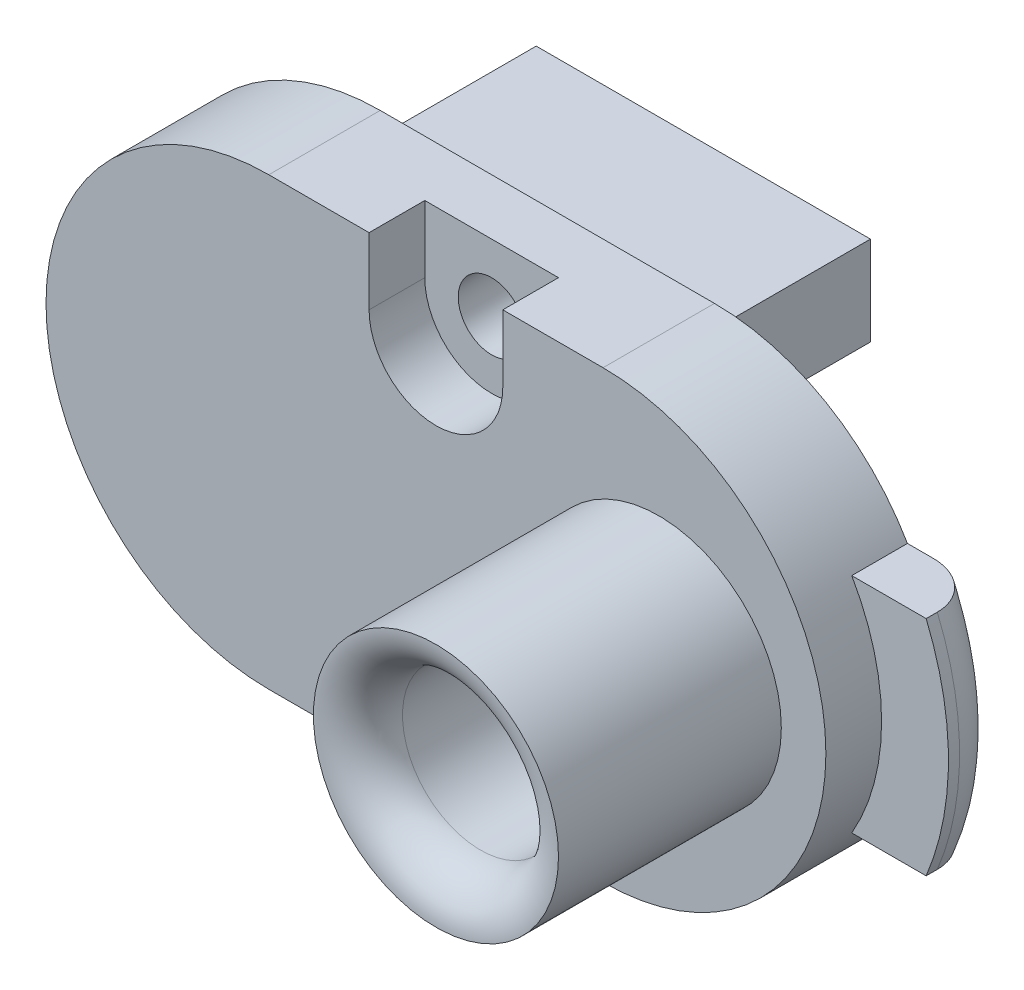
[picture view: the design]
ISO-10303-21;
HEADER;
FILE_DESCRIPTION(('STEP AP214'),'2;1');
FILE_NAME('part.step','',(''),(''),'','','');
FILE_SCHEMA(('AUTOMOTIVE_DESIGN { 1 0 10303 214 1 1 1 1 }'));
ENDSEC;
DATA;
#1=APPLICATION_CONTEXT('core data for automotive mechanical design processes');
#2=APPLICATION_PROTOCOL_DEFINITION('international standard','automotive_design',2000,#1);
#3=PRODUCT_CONTEXT('',#1,'mechanical');
#4=PRODUCT('Part','Part','',(#3));
#5=PRODUCT_RELATED_PRODUCT_CATEGORY('part','',(#4));
#6=PRODUCT_DEFINITION_FORMATION('','',#4);
#7=PRODUCT_DEFINITION_CONTEXT('part definition',#1,'design');
#8=PRODUCT_DEFINITION('design','',#6,#7);
#9=PRODUCT_DEFINITION_SHAPE('','',#8);
#10=(LENGTH_UNIT() NAMED_UNIT(*) SI_UNIT(.MILLI.,.METRE.));
#11=(NAMED_UNIT(*) PLANE_ANGLE_UNIT() SI_UNIT($,.RADIAN.));
#12=(NAMED_UNIT(*) SI_UNIT($,.STERADIAN.) SOLID_ANGLE_UNIT());
#13=UNCERTAINTY_MEASURE_WITH_UNIT(LENGTH_MEASURE(1.E-05),#10,'distance_accuracy_value','');
#14=(GEOMETRIC_REPRESENTATION_CONTEXT(3) GLOBAL_UNCERTAINTY_ASSIGNED_CONTEXT((#13)) GLOBAL_UNIT_ASSIGNED_CONTEXT((#10,
#11,#12)) REPRESENTATION_CONTEXT('',''));
#15=CARTESIAN_POINT('',(0.,0.,0.));
#16=DIRECTION('',(0.,0.,1.));
#17=DIRECTION('',(1.,0.,0.));
#18=AXIS2_PLACEMENT_3D('',#15,#16,#17);
#19=CARTESIAN_POINT('',(7.5,-9.,-9.5));
#20=DIRECTION('',(-1.,0.,0.));
#21=DIRECTION('',(0.,0.,1.));
#22=AXIS2_PLACEMENT_3D('',#19,#20,#21);
#23=PLANE('',#22);
#24=DIRECTION('',(0.,-1.,0.));
#25=VECTOR('',#24,1.);
#26=CARTESIAN_POINT('',(7.5,-5.,-4.5));
#27=LINE('',#26,#25);
#28=CARTESIAN_POINT('',(7.5,-4.89897948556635,-4.5));
#29=VERTEX_POINT('',#28);
#30=CARTESIAN_POINT('',(7.5,-5.,-4.5));
#31=VERTEX_POINT('',#30);
#32=EDGE_CURVE('E346',#29,#31,#27,.T.);
#33=ORIENTED_EDGE('',*,*,#32,.F.);
#34=DIRECTION('',(0.,0.,-1.));
#35=VECTOR('',#34,1.);
#36=CARTESIAN_POINT('',(7.5,-4.89897948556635,13.056349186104));
#37=LINE('',#36,#35);
#38=CARTESIAN_POINT('',(7.5,-4.89897948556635,-2.5));
#39=VERTEX_POINT('',#38);
#40=EDGE_CURVE('E285',#29,#39,#37,.F.);
#41=ORIENTED_EDGE('',*,*,#40,.T.);
#42=DIRECTION('',(0.,-1.,0.));
#43=VECTOR('',#42,1.);
#44=CARTESIAN_POINT('',(7.5,-9.,-2.5));
#45=LINE('',#44,#43);
#46=CARTESIAN_POINT('',(7.5,-9.,-2.5));
#47=VERTEX_POINT('',#46);
#48=EDGE_CURVE('E435',#39,#47,#45,.T.);
#49=ORIENTED_EDGE('',*,*,#48,.T.);
#50=DIRECTION('',(0.,0.,1.));
#51=VECTOR('',#50,1.);
#52=CARTESIAN_POINT('',(7.5,-9.,-9.5));
#53=LINE('',#52,#51);
#54=CARTESIAN_POINT('',(7.5,-9.,-9.5));
#55=VERTEX_POINT('',#54);
#56=EDGE_CURVE('E464',#55,#47,#53,.T.);
#57=ORIENTED_EDGE('',*,*,#56,.F.);
#58=DIRECTION('',(0.,-1.,0.));
#59=VECTOR('',#58,1.);
#60=CARTESIAN_POINT('',(7.5,-9.,-9.5));
#61=LINE('',#60,#59);
#62=CARTESIAN_POINT('',(7.5,-5.,-9.5));
#63=VERTEX_POINT('',#62);
#64=EDGE_CURVE('E448',#63,#55,#61,.T.);
#65=ORIENTED_EDGE('',*,*,#64,.F.);
#66=DIRECTION('',(0.,0.,-1.));
#67=VECTOR('',#66,1.);
#68=CARTESIAN_POINT('',(7.5,-5.,-4.5));
#69=LINE('',#68,#67);
#70=EDGE_CURVE('E358',#31,#63,#69,.T.);
#71=ORIENTED_EDGE('',*,*,#70,.F.);
#72=EDGE_LOOP('',(#33,#41,#49,#57,#65,#71));
#73=FACE_BOUND('',#72,.T.);
#74=ADVANCED_FACE('F36',(#73),#23,.F.);
#75=CARTESIAN_POINT('',(7.5,0.,2.5));
#76=DIRECTION('',(0.,0.,1.));
#77=DIRECTION('',(1.,0.,0.));
#78=AXIS2_PLACEMENT_3D('',#75,#76,#77);
#79=PLANE('',#78);
#80=DIRECTION('',(0.,-1.,0.));
#81=VECTOR('',#80,1.);
#82=CARTESIAN_POINT('',(-3.,7.,2.5));
#83=LINE('',#82,#81);
#84=CARTESIAN_POINT('',(-3.,10.,2.5));
#85=VERTEX_POINT('',#84);
#86=CARTESIAN_POINT('',(-3.,7.,2.5));
#87=VERTEX_POINT('',#86);
#88=EDGE_CURVE('E379',#85,#87,#83,.T.);
#89=ORIENTED_EDGE('',*,*,#88,.F.);
#90=DIRECTION('',(-1.,0.,0.));
#91=VECTOR('',#90,1.);
#92=CARTESIAN_POINT('',(-7.5,10.,2.5));
#93=LINE('',#92,#91);
#94=CARTESIAN_POINT('',(-7.5,10.,2.5));
#95=VERTEX_POINT('',#94);
#96=EDGE_CURVE('E481',#85,#95,#93,.T.);
#97=ORIENTED_EDGE('',*,*,#96,.T.);
#98=CARTESIAN_POINT('',(-7.5,0.,2.5));
#99=DIRECTION('',(0.,0.,1.));
#100=DIRECTION('',(1.,0.,0.));
#101=AXIS2_PLACEMENT_3D('',#98,#99,#100);
#102=CIRCLE('',#101,10.);
#103=CARTESIAN_POINT('',(-7.5,-10.,2.5));
#104=VERTEX_POINT('',#103);
#105=EDGE_CURVE('E485',#95,#104,#102,.T.);
#106=ORIENTED_EDGE('',*,*,#105,.T.);
#107=DIRECTION('',(1.,0.,0.));
#108=VECTOR('',#107,1.);
#109=CARTESIAN_POINT('',(-7.5,-10.,2.5));
#110=LINE('',#109,#108);
#111=CARTESIAN_POINT('',(-3.,-10.,2.5));
#112=VERTEX_POINT('',#111);
#113=EDGE_CURVE('E488',#104,#112,#110,.T.);
#114=ORIENTED_EDGE('',*,*,#113,.T.);
#115=DIRECTION('',(0.,-1.,0.));
#116=VECTOR('',#115,1.);
#117=CARTESIAN_POINT('',(-3.,-7.,2.5));
#118=LINE('',#117,#116);
#119=CARTESIAN_POINT('',(-3.,-7.,2.5));
#120=VERTEX_POINT('',#119);
#121=EDGE_CURVE('E409',#120,#112,#118,.T.);
#122=ORIENTED_EDGE('',*,*,#121,.F.);
#123=CARTESIAN_POINT('',(0.,-7.,2.5));
#124=DIRECTION('',(0.,0.,1.));
#125=DIRECTION('',(1.,0.,0.));
#126=AXIS2_PLACEMENT_3D('',#123,#124,#125);
#127=CIRCLE('',#126,3.);
#128=CARTESIAN_POINT('',(3.,-7.,2.5));
#129=VERTEX_POINT('',#128);
#130=EDGE_CURVE('E406',#129,#120,#127,.T.);
#131=ORIENTED_EDGE('',*,*,#130,.F.);
#132=DIRECTION('',(0.,1.,0.));
#133=VECTOR('',#132,1.);
#134=CARTESIAN_POINT('',(3.,-7.,2.5));
#135=LINE('',#134,#133);
#136=CARTESIAN_POINT('',(3.,-10.,2.5));
#137=VERTEX_POINT('',#136);
#138=EDGE_CURVE('E396',#137,#129,#135,.T.);
#139=ORIENTED_EDGE('',*,*,#138,.F.);
#140=CARTESIAN_POINT('',(7.5,-10.,2.5));
#141=VERTEX_POINT('',#140);
#142=EDGE_CURVE('E487',#137,#141,#110,.T.);
#143=ORIENTED_EDGE('',*,*,#142,.T.);
#144=CARTESIAN_POINT('',(7.5,0.,2.5));
#145=DIRECTION('',(0.,0.,1.));
#146=DIRECTION('',(1.,0.,0.));
#147=AXIS2_PLACEMENT_3D('',#144,#145,#146);
#148=CIRCLE('',#147,10.);
#149=CARTESIAN_POINT('',(7.5,10.,2.5));
#150=VERTEX_POINT('',#149);
#151=EDGE_CURVE('E478',#141,#150,#148,.T.);
#152=ORIENTED_EDGE('',*,*,#151,.T.);
#153=CARTESIAN_POINT('',(3.,10.,2.5));
#154=VERTEX_POINT('',#153);
#155=EDGE_CURVE('E482',#150,#154,#93,.T.);
#156=ORIENTED_EDGE('',*,*,#155,.T.);
#157=DIRECTION('',(0.,1.,0.));
#158=VECTOR('',#157,1.);
#159=CARTESIAN_POINT('',(3.,7.,2.5));
#160=LINE('',#159,#158);
#161=CARTESIAN_POINT('',(3.,7.,2.5));
#162=VERTEX_POINT('',#161);
#163=EDGE_CURVE('E377',#162,#154,#160,.T.);
#164=ORIENTED_EDGE('',*,*,#163,.F.);
#165=CARTESIAN_POINT('',(0.,7.,2.5));
#166=DIRECTION('',(0.,0.,1.));
#167=DIRECTION('',(-1.,0.,0.));
#168=AXIS2_PLACEMENT_3D('',#165,#166,#167);
#169=CIRCLE('',#168,3.);
#170=EDGE_CURVE('E375',#87,#162,#169,.T.);
#171=ORIENTED_EDGE('',*,*,#170,.F.);
#172=EDGE_LOOP('',(#89,#97,#106,#114,#122,#131,#139,#143,#152,#156,#164,#171));
#173=FACE_BOUND('',#172,.T.);
#174=CARTESIAN_POINT('',(10.,0.,2.5));
#175=DIRECTION('',(0.,0.,1.));
#176=DIRECTION('',(1.,0.,0.));
#177=AXIS2_PLACEMENT_3D('',#174,#175,#176);
#178=CIRCLE('',#177,5.5);
#179=CARTESIAN_POINT('',(15.5,0.,2.5));
#180=VERTEX_POINT('',#179);
#181=EDGE_CURVE('E288',#180,#180,#178,.T.);
#182=ORIENTED_EDGE('',*,*,#181,.F.);
#183=EDGE_LOOP('',(#182));
#184=FACE_BOUND('',#183,.T.);
#185=ADVANCED_FACE('F653',(#173,#184),#79,.T.);
#186=CARTESIAN_POINT('',(7.5,9.,-9.5));
#187=DIRECTION('',(0.,0.,1.));
#188=DIRECTION('',(1.,0.,0.));
#189=AXIS2_PLACEMENT_3D('',#186,#187,#188);
#190=PLANE('',#189);
#191=CARTESIAN_POINT('',(0.,-7.,-9.5));
#192=DIRECTION('',(0.,0.,1.));
#193=DIRECTION('',(1.,0.,0.));
#194=AXIS2_PLACEMENT_3D('',#191,#192,#193);
#195=CIRCLE('',#194,1.5);
#196=CARTESIAN_POINT('',(1.5,-7.,-9.5));
#197=VERTEX_POINT('',#196);
#198=EDGE_CURVE('E366',#197,#197,#195,.T.);
#199=ORIENTED_EDGE('',*,*,#198,.T.);
#200=EDGE_LOOP('',(#199));
#201=FACE_BOUND('',#200,.T.);
#202=DIRECTION('',(0.,1.,0.));
#203=VECTOR('',#202,1.);
#204=CARTESIAN_POINT('',(-7.5,9.,-9.5));
#205=LINE('',#204,#203);
#206=CARTESIAN_POINT('',(-7.5,-9.,-9.5));
#207=VERTEX_POINT('',#206);
#208=CARTESIAN_POINT('',(-7.5,-5.,-9.5));
#209=VERTEX_POINT('',#208);
#210=EDGE_CURVE('E455',#207,#209,#205,.T.);
#211=ORIENTED_EDGE('',*,*,#210,.T.);
#212=DIRECTION('',(-1.,0.,0.));
#213=VECTOR('',#212,1.);
#214=CARTESIAN_POINT('',(-7.5,-5.,-9.5));
#215=LINE('',#214,#213);
#216=EDGE_CURVE('E338',#63,#209,#215,.T.);
#217=ORIENTED_EDGE('',*,*,#216,.F.);
#218=ORIENTED_EDGE('',*,*,#64,.T.);
#219=DIRECTION('',(-1.,0.,0.));
#220=VECTOR('',#219,1.);
#221=CARTESIAN_POINT('',(7.5,-9.,-9.5));
#222=LINE('',#221,#220);
#223=EDGE_CURVE('E452',#55,#207,#222,.T.);
#224=ORIENTED_EDGE('',*,*,#223,.T.);
#225=EDGE_LOOP('',(#211,#217,#218,#224));
#226=FACE_BOUND('',#225,.T.);
#227=ADVANCED_FACE('F632',(#201,#226),#190,.F.);
#228=CARTESIAN_POINT('',(7.5,0.,-2.5));
#229=DIRECTION('',(0.,0.,1.));
#230=DIRECTION('',(1.,0.,0.));
#231=AXIS2_PLACEMENT_3D('',#228,#229,#230);
#232=PLANE('',#231);
#233=ORIENTED_EDGE('',*,*,#48,.F.);
#234=CARTESIAN_POINT('',(10.,0.,-2.5));
#235=DIRECTION('',(0.,0.,1.));
#236=DIRECTION('',(1.,0.,0.));
#237=AXIS2_PLACEMENT_3D('',#234,#235,#236);
#238=CIRCLE('',#237,5.5);
#239=CARTESIAN_POINT('',(7.5,4.89897948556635,-2.5));
#240=VERTEX_POINT('',#239);
#241=EDGE_CURVE('E514',#39,#240,#238,.T.);
#242=ORIENTED_EDGE('',*,*,#241,.T.);
#243=CARTESIAN_POINT('',(7.5,9.,-2.5));
#244=VERTEX_POINT('',#243);
#245=EDGE_CURVE('E436',#244,#240,#45,.T.);
#246=ORIENTED_EDGE('',*,*,#245,.F.);
#247=DIRECTION('',(1.,0.,0.));
#248=VECTOR('',#247,1.);
#249=CARTESIAN_POINT('',(-7.5,9.,-2.5));
#250=LINE('',#249,#248);
#251=CARTESIAN_POINT('',(-7.5,9.,-2.5));
#252=VERTEX_POINT('',#251);
#253=EDGE_CURVE('E427',#252,#244,#250,.T.);
#254=ORIENTED_EDGE('',*,*,#253,.F.);
#255=CARTESIAN_POINT('',(-7.5,0.,-2.5));
#256=DIRECTION('',(0.,0.,-1.));
#257=DIRECTION('',(1.,0.,0.));
#258=AXIS2_PLACEMENT_3D('',#255,#256,#257);
#259=CIRCLE('',#258,9.);
#260=CARTESIAN_POINT('',(-16.4861003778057,0.5,-2.5));
#261=VERTEX_POINT('',#260);
#262=EDGE_CURVE('E297',#261,#252,#259,.T.);
#263=ORIENTED_EDGE('',*,*,#262,.F.);
#264=DIRECTION('',(-1.,0.,0.));
#265=VECTOR('',#264,1.);
#266=CARTESIAN_POINT('',(-7.5,0.5,-2.5));
#267=LINE('',#266,#265);
#268=CARTESIAN_POINT('',(-7.5,0.5,-2.5));
#269=VERTEX_POINT('',#268);
#270=EDGE_CURVE('E294',#269,#261,#267,.T.);
#271=ORIENTED_EDGE('',*,*,#270,.F.);
#272=DIRECTION('',(0.,1.,0.));
#273=VECTOR('',#272,1.);
#274=CARTESIAN_POINT('',(-7.5,9.,-2.5));
#275=LINE('',#274,#273);
#276=CARTESIAN_POINT('',(-7.5,-0.499999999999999,-2.5));
#277=VERTEX_POINT('',#276);
#278=EDGE_CURVE('E442',#277,#269,#275,.T.);
#279=ORIENTED_EDGE('',*,*,#278,.F.);
#280=DIRECTION('',(1.,0.,0.));
#281=VECTOR('',#280,1.);
#282=CARTESIAN_POINT('',(-7.5,-0.5,-2.5));
#283=LINE('',#282,#281);
#284=CARTESIAN_POINT('',(-16.4861003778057,-0.5,-2.5));
#285=VERTEX_POINT('',#284);
#286=EDGE_CURVE('E318',#285,#277,#283,.T.);
#287=ORIENTED_EDGE('',*,*,#286,.F.);
#288=CARTESIAN_POINT('',(-7.5,0.,-2.5));
#289=DIRECTION('',(0.,0.,-1.));
#290=DIRECTION('',(1.,0.,0.));
#291=AXIS2_PLACEMENT_3D('',#288,#289,#290);
#292=CIRCLE('',#291,9.);
#293=CARTESIAN_POINT('',(-7.5,-9.,-2.5));
#294=VERTEX_POINT('',#293);
#295=EDGE_CURVE('E312',#294,#285,#292,.T.);
#296=ORIENTED_EDGE('',*,*,#295,.F.);
#297=DIRECTION('',(-1.,0.,0.));
#298=VECTOR('',#297,1.);
#299=CARTESIAN_POINT('',(7.5,-9.,-2.5));
#300=LINE('',#299,#298);
#301=EDGE_CURVE('E439',#47,#294,#300,.T.);
#302=ORIENTED_EDGE('',*,*,#301,.F.);
#303=EDGE_LOOP('',(#233,#242,#246,#254,#263,#271,#279,#287,#296,#302));
#304=FACE_BOUND('',#303,.T.);
#305=DIRECTION('',(-1.,0.,0.));
#306=VECTOR('',#305,1.);
#307=CARTESIAN_POINT('',(16.1602540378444,5.,-2.5));
#308=LINE('',#307,#306);
#309=CARTESIAN_POINT('',(17.2979589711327,5.,-2.5));
#310=VERTEX_POINT('',#309);
#311=CARTESIAN_POINT('',(16.1602540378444,5.,-2.5));
#312=VERTEX_POINT('',#311);
#313=EDGE_CURVE('E270',#310,#312,#308,.T.);
#314=ORIENTED_EDGE('',*,*,#313,.F.);
#315=CARTESIAN_POINT('',(7.5,0.,-2.5));
#316=DIRECTION('',(0.,0.,1.));
#317=DIRECTION('',(1.,0.,0.));
#318=AXIS2_PLACEMENT_3D('',#315,#316,#317);
#319=CIRCLE('',#318,11.);
#320=CARTESIAN_POINT('',(17.2979589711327,-5.,-2.5));
#321=VERTEX_POINT('',#320);
#322=EDGE_CURVE('E51',#310,#321,#319,.F.);
#323=ORIENTED_EDGE('',*,*,#322,.T.);
#324=DIRECTION('',(1.,0.,0.));
#325=VECTOR('',#324,1.);
#326=CARTESIAN_POINT('',(16.1602540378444,-5.,-2.5));
#327=LINE('',#326,#325);
#328=CARTESIAN_POINT('',(16.1602540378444,-5.,-2.5));
#329=VERTEX_POINT('',#328);
#330=EDGE_CURVE('E274',#329,#321,#327,.T.);
#331=ORIENTED_EDGE('',*,*,#330,.F.);
#332=CARTESIAN_POINT('',(7.5,0.,-2.5));
#333=DIRECTION('',(0.,0.,1.));
#334=DIRECTION('',(1.,0.,0.));
#335=AXIS2_PLACEMENT_3D('',#332,#333,#334);
#336=CIRCLE('',#335,10.);
#337=CARTESIAN_POINT('',(7.5,-10.,-2.5));
#338=VERTEX_POINT('',#337);
#339=EDGE_CURVE('E269',#338,#329,#336,.T.);
#340=ORIENTED_EDGE('',*,*,#339,.F.);
#341=DIRECTION('',(1.,0.,0.));
#342=VECTOR('',#341,1.);
#343=CARTESIAN_POINT('',(-7.5,-10.,-2.5));
#344=LINE('',#343,#342);
#345=CARTESIAN_POINT('',(-7.5,-10.,-2.5));
#346=VERTEX_POINT('',#345);
#347=EDGE_CURVE('E476',#346,#338,#344,.T.);
#348=ORIENTED_EDGE('',*,*,#347,.F.);
#349=CARTESIAN_POINT('',(-7.5,0.,-2.5));
#350=DIRECTION('',(0.,0.,1.));
#351=DIRECTION('',(1.,0.,0.));
#352=AXIS2_PLACEMENT_3D('',#349,#350,#351);
#353=CIRCLE('',#352,10.);
#354=CARTESIAN_POINT('',(-7.5,10.,-2.5));
#355=VERTEX_POINT('',#354);
#356=EDGE_CURVE('E474',#355,#346,#353,.T.);
#357=ORIENTED_EDGE('',*,*,#356,.F.);
#358=DIRECTION('',(-1.,0.,0.));
#359=VECTOR('',#358,1.);
#360=CARTESIAN_POINT('',(-7.5,10.,-2.5));
#361=LINE('',#360,#359);
#362=CARTESIAN_POINT('',(7.5,10.,-2.5));
#363=VERTEX_POINT('',#362);
#364=EDGE_CURVE('E472',#363,#355,#361,.T.);
#365=ORIENTED_EDGE('',*,*,#364,.F.);
#366=EDGE_CURVE('E470',#312,#363,#336,.T.);
#367=ORIENTED_EDGE('',*,*,#366,.F.);
#368=EDGE_LOOP('',(#314,#323,#331,#340,#348,#357,#365,#367));
#369=FACE_BOUND('',#368,.T.);
#370=ADVANCED_FACE('F649',(#304,#369),#232,.F.);
#371=CARTESIAN_POINT('',(7.5,0.,2.5));
#372=DIRECTION('',(0.,0.,-1.));
#373=DIRECTION('',(-1.,0.,0.));
#374=AXIS2_PLACEMENT_3D('',#371,#372,#373);
#375=CYLINDRICAL_SURFACE('',#374,10.);
#376=CARTESIAN_POINT('',(7.5,0.,0.));
#377=DIRECTION('',(0.,0.,-1.));
#378=DIRECTION('',(1.,0.,0.));
#379=AXIS2_PLACEMENT_3D('',#376,#377,#378);
#380=CIRCLE('',#379,10.);
#381=CARTESIAN_POINT('',(16.1602540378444,5.,0.));
#382=VERTEX_POINT('',#381);
#383=CARTESIAN_POINT('',(16.1602540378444,-5.,0.));
#384=VERTEX_POINT('',#383);
#385=EDGE_CURVE('E256',#382,#384,#380,.T.);
#386=ORIENTED_EDGE('',*,*,#385,.F.);
#387=DIRECTION('',(0.,0.,1.));
#388=VECTOR('',#387,1.);
#389=CARTESIAN_POINT('',(16.1602540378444,5.,-2.5));
#390=LINE('',#389,#388);
#391=EDGE_CURVE('E282',#312,#382,#390,.T.);
#392=ORIENTED_EDGE('',*,*,#391,.F.);
#393=ORIENTED_EDGE('',*,*,#366,.T.);
#394=DIRECTION('',(0.,0.,-1.));
#395=VECTOR('',#394,1.);
#396=CARTESIAN_POINT('',(7.5,10.,2.5));
#397=LINE('',#396,#395);
#398=EDGE_CURVE('E499',#150,#363,#397,.T.);
#399=ORIENTED_EDGE('',*,*,#398,.F.);
#400=ORIENTED_EDGE('',*,*,#151,.F.);
#401=DIRECTION('',(0.,0.,-1.));
#402=VECTOR('',#401,1.);
#403=CARTESIAN_POINT('',(7.5,-10.,2.5));
#404=LINE('',#403,#402);
#405=EDGE_CURVE('E491',#141,#338,#404,.T.);
#406=ORIENTED_EDGE('',*,*,#405,.T.);
#407=ORIENTED_EDGE('',*,*,#339,.T.);
#408=DIRECTION('',(0.,0.,1.));
#409=VECTOR('',#408,1.);
#410=CARTESIAN_POINT('',(16.1602540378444,-5.,-2.5));
#411=LINE('',#410,#409);
#412=EDGE_CURVE('E249',#329,#384,#411,.T.);
#413=ORIENTED_EDGE('',*,*,#412,.T.);
#414=EDGE_LOOP('',(#386,#392,#393,#399,#400,#406,#407,#413));
#415=FACE_BOUND('',#414,.T.);
#416=ADVANCED_FACE('F38',(#415),#375,.T.);
#417=CARTESIAN_POINT('',(-7.5,10.,2.5));
#418=DIRECTION('',(0.,-1.,0.));
#419=DIRECTION('',(0.,0.,-1.));
#420=AXIS2_PLACEMENT_3D('',#417,#418,#419);
#421=PLANE('',#420);
#422=ORIENTED_EDGE('',*,*,#96,.F.);
#423=DIRECTION('',(0.,0.,1.));
#424=VECTOR('',#423,1.);
#425=CARTESIAN_POINT('',(-3.,10.,0.));
#426=LINE('',#425,#424);
#427=CARTESIAN_POINT('',(-3.,10.,0.));
#428=VERTEX_POINT('',#427);
#429=EDGE_CURVE('E397',#428,#85,#426,.T.);
#430=ORIENTED_EDGE('',*,*,#429,.F.);
#431=DIRECTION('',(-1.,0.,0.));
#432=VECTOR('',#431,1.);
#433=CARTESIAN_POINT('',(-3.,10.,0.));
#434=LINE('',#433,#432);
#435=CARTESIAN_POINT('',(3.,10.,0.));
#436=VERTEX_POINT('',#435);
#437=EDGE_CURVE('E388',#436,#428,#434,.T.);
#438=ORIENTED_EDGE('',*,*,#437,.F.);
#439=DIRECTION('',(0.,0.,1.));
#440=VECTOR('',#439,1.);
#441=CARTESIAN_POINT('',(3.,10.,0.));
#442=LINE('',#441,#440);
#443=EDGE_CURVE('E399',#436,#154,#442,.T.);
#444=ORIENTED_EDGE('',*,*,#443,.T.);
#445=ORIENTED_EDGE('',*,*,#155,.F.);
#446=ORIENTED_EDGE('',*,*,#398,.T.);
#447=ORIENTED_EDGE('',*,*,#364,.T.);
#448=DIRECTION('',(0.,0.,-1.));
#449=VECTOR('',#448,1.);
#450=CARTESIAN_POINT('',(-7.5,10.,2.5));
#451=LINE('',#450,#449);
#452=EDGE_CURVE('E496',#95,#355,#451,.T.);
#453=ORIENTED_EDGE('',*,*,#452,.F.);
#454=EDGE_LOOP('',(#422,#430,#438,#444,#445,#446,#447,#453));
#455=FACE_BOUND('',#454,.T.);
#456=ADVANCED_FACE('F662',(#455),#421,.F.);
#457=CARTESIAN_POINT('',(-7.5,0.,2.5));
#458=DIRECTION('',(0.,0.,-1.));
#459=DIRECTION('',(-1.,0.,0.));
#460=AXIS2_PLACEMENT_3D('',#457,#458,#459);
#461=CYLINDRICAL_SURFACE('',#460,10.);
#462=ORIENTED_EDGE('',*,*,#356,.T.);
#463=DIRECTION('',(0.,0.,-1.));
#464=VECTOR('',#463,1.);
#465=CARTESIAN_POINT('',(-7.5,-10.,2.5));
#466=LINE('',#465,#464);
#467=EDGE_CURVE('E493',#104,#346,#466,.T.);
#468=ORIENTED_EDGE('',*,*,#467,.F.);
#469=ORIENTED_EDGE('',*,*,#105,.F.);
#470=ORIENTED_EDGE('',*,*,#452,.T.);
#471=EDGE_LOOP('',(#462,#468,#469,#470));
#472=FACE_BOUND('',#471,.T.);
#473=ADVANCED_FACE('F659',(#472),#461,.T.);
#474=CARTESIAN_POINT('',(-7.5,-10.,2.5));
#475=DIRECTION('',(0.,1.,0.));
#476=DIRECTION('',(0.,0.,1.));
#477=AXIS2_PLACEMENT_3D('',#474,#475,#476);
#478=PLANE('',#477);
#479=DIRECTION('',(1.,0.,0.));
#480=VECTOR('',#479,1.);
#481=CARTESIAN_POINT('',(-3.,-10.,0.));
#482=LINE('',#481,#480);
#483=CARTESIAN_POINT('',(-3.,-10.,0.));
#484=VERTEX_POINT('',#483);
#485=CARTESIAN_POINT('',(3.,-10.,0.));
#486=VERTEX_POINT('',#485);
#487=EDGE_CURVE('E411',#484,#486,#482,.T.);
#488=ORIENTED_EDGE('',*,*,#487,.F.);
#489=DIRECTION('',(0.,0.,1.));
#490=VECTOR('',#489,1.);
#491=CARTESIAN_POINT('',(-3.,-10.,0.));
#492=LINE('',#491,#490);
#493=EDGE_CURVE('E424',#484,#112,#492,.T.);
#494=ORIENTED_EDGE('',*,*,#493,.T.);
#495=ORIENTED_EDGE('',*,*,#113,.F.);
#496=ORIENTED_EDGE('',*,*,#467,.T.);
#497=ORIENTED_EDGE('',*,*,#347,.T.);
#498=ORIENTED_EDGE('',*,*,#405,.F.);
#499=ORIENTED_EDGE('',*,*,#142,.F.);
#500=DIRECTION('',(0.,0.,1.));
#501=VECTOR('',#500,1.);
#502=CARTESIAN_POINT('',(3.,-10.,0.));
#503=LINE('',#502,#501);
#504=EDGE_CURVE('E423',#486,#137,#503,.T.);
#505=ORIENTED_EDGE('',*,*,#504,.F.);
#506=EDGE_LOOP('',(#488,#494,#495,#496,#497,#498,#499,#505));
#507=FACE_BOUND('',#506,.T.);
#508=ADVANCED_FACE('F647',(#507),#478,.F.);
#509=CARTESIAN_POINT('',(-7.5,9.,-9.5));
#510=DIRECTION('',(0.,-1.,0.));
#511=DIRECTION('',(0.,0.,-1.));
#512=AXIS2_PLACEMENT_3D('',#509,#510,#511);
#513=PLANE('',#512);
#514=ORIENTED_EDGE('',*,*,#253,.T.);
#515=DIRECTION('',(0.,0.,1.));
#516=VECTOR('',#515,1.);
#517=CARTESIAN_POINT('',(7.5,9.,-9.5));
#518=LINE('',#517,#516);
#519=CARTESIAN_POINT('',(7.5,9.,-9.5));
#520=VERTEX_POINT('',#519);
#521=EDGE_CURVE('E467',#520,#244,#518,.T.);
#522=ORIENTED_EDGE('',*,*,#521,.F.);
#523=DIRECTION('',(1.,0.,0.));
#524=VECTOR('',#523,1.);
#525=CARTESIAN_POINT('',(-7.5,9.,-9.5));
#526=LINE('',#525,#524);
#527=CARTESIAN_POINT('',(-7.5,9.,-9.5));
#528=VERTEX_POINT('',#527);
#529=EDGE_CURVE('E445',#528,#520,#526,.T.);
#530=ORIENTED_EDGE('',*,*,#529,.F.);
#531=DIRECTION('',(0.,0.,1.));
#532=VECTOR('',#531,1.);
#533=CARTESIAN_POINT('',(-7.5,9.,-9.5));
#534=LINE('',#533,#532);
#535=EDGE_CURVE('E458',#528,#252,#534,.T.);
#536=ORIENTED_EDGE('',*,*,#535,.T.);
#537=EDGE_LOOP('',(#514,#522,#530,#536));
#538=FACE_BOUND('',#537,.T.);
#539=ADVANCED_FACE('F643',(#538),#513,.F.);
#540=ORIENTED_EDGE('',*,*,#245,.T.);
#541=DIRECTION('',(0.,0.,-1.));
#542=VECTOR('',#541,1.);
#543=CARTESIAN_POINT('',(7.5,4.89897948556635,13.056349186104));
#544=LINE('',#543,#542);
#545=CARTESIAN_POINT('',(7.5,4.89897948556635,-4.5));
#546=VERTEX_POINT('',#545);
#547=EDGE_CURVE('E281',#240,#546,#544,.T.);
#548=ORIENTED_EDGE('',*,*,#547,.T.);
#549=CARTESIAN_POINT('',(7.5,5.,-4.5));
#550=VERTEX_POINT('',#549);
#551=EDGE_CURVE('E347',#550,#546,#27,.T.);
#552=ORIENTED_EDGE('',*,*,#551,.F.);
#553=DIRECTION('',(0.,0.,-1.));
#554=VECTOR('',#553,1.);
#555=CARTESIAN_POINT('',(7.5,5.,-4.5));
#556=LINE('',#555,#554);
#557=CARTESIAN_POINT('',(7.5,5.,-9.5));
#558=VERTEX_POINT('',#557);
#559=EDGE_CURVE('E360',#550,#558,#556,.T.);
#560=ORIENTED_EDGE('',*,*,#559,.T.);
#561=EDGE_CURVE('E449',#520,#558,#61,.T.);
#562=ORIENTED_EDGE('',*,*,#561,.F.);
#563=ORIENTED_EDGE('',*,*,#521,.T.);
#564=EDGE_LOOP('',(#540,#548,#552,#560,#562,#563));
#565=FACE_BOUND('',#564,.T.);
#566=ADVANCED_FACE('F639',(#565),#23,.F.);
#567=CARTESIAN_POINT('',(7.5,-9.,-9.5));
#568=DIRECTION('',(0.,1.,0.));
#569=DIRECTION('',(0.,0.,1.));
#570=AXIS2_PLACEMENT_3D('',#567,#568,#569);
#571=PLANE('',#570);
#572=ORIENTED_EDGE('',*,*,#301,.T.);
#573=DIRECTION('',(0.,0.,1.));
#574=VECTOR('',#573,1.);
#575=CARTESIAN_POINT('',(-7.5,-9.,-9.5));
#576=LINE('',#575,#574);
#577=EDGE_CURVE('E461',#207,#294,#576,.T.);
#578=ORIENTED_EDGE('',*,*,#577,.F.);
#579=ORIENTED_EDGE('',*,*,#223,.F.);
#580=ORIENTED_EDGE('',*,*,#56,.T.);
#581=EDGE_LOOP('',(#572,#578,#579,#580));
#582=FACE_BOUND('',#581,.T.);
#583=ADVANCED_FACE('F635',(#582),#571,.F.);
#584=CARTESIAN_POINT('',(-7.5,9.,-9.5));
#585=DIRECTION('',(1.,0.,0.));
#586=DIRECTION('',(0.,1.,0.));
#587=AXIS2_PLACEMENT_3D('',#584,#585,#586);
#588=PLANE('',#587);
#589=DIRECTION('',(0.,1.,0.));
#590=VECTOR('',#589,1.);
#591=CARTESIAN_POINT('',(-7.5,-5.,-4.5));
#592=LINE('',#591,#590);
#593=CARTESIAN_POINT('',(-7.5,-5.,-4.5));
#594=VERTEX_POINT('',#593);
#595=CARTESIAN_POINT('',(-7.5,5.,-4.5));
#596=VERTEX_POINT('',#595);
#597=EDGE_CURVE('E340',#594,#596,#592,.T.);
#598=ORIENTED_EDGE('',*,*,#597,.F.);
#599=DIRECTION('',(0.,0.,-1.));
#600=VECTOR('',#599,1.);
#601=CARTESIAN_POINT('',(-7.5,-5.,-4.5));
#602=LINE('',#601,#600);
#603=EDGE_CURVE('E354',#594,#209,#602,.T.);
#604=ORIENTED_EDGE('',*,*,#603,.T.);
#605=ORIENTED_EDGE('',*,*,#210,.F.);
#606=ORIENTED_EDGE('',*,*,#577,.T.);
#607=DIRECTION('',(0.,0.,-1.));
#608=VECTOR('',#607,1.);
#609=CARTESIAN_POINT('',(-7.5,-9.,-0.5));
#610=LINE('',#609,#608);
#611=CARTESIAN_POINT('',(-7.5,-9.,-0.5));
#612=VERTEX_POINT('',#611);
#613=EDGE_CURVE('E330',#612,#294,#610,.T.);
#614=ORIENTED_EDGE('',*,*,#613,.F.);
#615=DIRECTION('',(0.,-1.,0.));
#616=VECTOR('',#615,1.);
#617=CARTESIAN_POINT('',(-7.5,-9.,-0.5));
#618=LINE('',#617,#616);
#619=CARTESIAN_POINT('',(-7.5,-0.5,-0.5));
#620=VERTEX_POINT('',#619);
#621=EDGE_CURVE('E326',#620,#612,#618,.T.);
#622=ORIENTED_EDGE('',*,*,#621,.F.);
#623=DIRECTION('',(0.,0.,-1.));
#624=VECTOR('',#623,1.);
#625=CARTESIAN_POINT('',(-7.5,-0.5,-0.5));
#626=LINE('',#625,#624);
#627=EDGE_CURVE('E333',#620,#277,#626,.T.);
#628=ORIENTED_EDGE('',*,*,#627,.T.);
#629=ORIENTED_EDGE('',*,*,#278,.T.);
#630=DIRECTION('',(0.,0.,-1.));
#631=VECTOR('',#630,1.);
#632=CARTESIAN_POINT('',(-7.5,0.5,-0.5));
#633=LINE('',#632,#631);
#634=CARTESIAN_POINT('',(-7.5,0.5,-0.5));
#635=VERTEX_POINT('',#634);
#636=EDGE_CURVE('E308',#635,#269,#633,.T.);
#637=ORIENTED_EDGE('',*,*,#636,.F.);
#638=DIRECTION('',(0.,-1.,0.));
#639=VECTOR('',#638,1.);
#640=CARTESIAN_POINT('',(-7.5,0.5,-0.5));
#641=LINE('',#640,#639);
#642=CARTESIAN_POINT('',(-7.5,9.,-0.5));
#643=VERTEX_POINT('',#642);
#644=EDGE_CURVE('E299',#643,#635,#641,.T.);
#645=ORIENTED_EDGE('',*,*,#644,.F.);
#646=DIRECTION('',(0.,0.,-1.));
#647=VECTOR('',#646,1.);
#648=CARTESIAN_POINT('',(-7.5,9.,-0.5));
#649=LINE('',#648,#647);
#650=EDGE_CURVE('E309',#643,#252,#649,.T.);
#651=ORIENTED_EDGE('',*,*,#650,.T.);
#652=ORIENTED_EDGE('',*,*,#535,.F.);
#653=CARTESIAN_POINT('',(-7.5,5.,-9.5));
#654=VERTEX_POINT('',#653);
#655=EDGE_CURVE('E454',#654,#528,#205,.T.);
#656=ORIENTED_EDGE('',*,*,#655,.F.);
#657=DIRECTION('',(0.,0.,-1.));
#658=VECTOR('',#657,1.);
#659=CARTESIAN_POINT('',(-7.5,5.,-4.5));
#660=LINE('',#659,#658);
#661=EDGE_CURVE('E353',#596,#654,#660,.T.);
#662=ORIENTED_EDGE('',*,*,#661,.F.);
#663=EDGE_LOOP('',(#598,#604,#605,#606,#614,#622,#628,#629,#637,#645,#651,#652,#656,#662));
#664=FACE_BOUND('',#663,.T.);
#665=ADVANCED_FACE('F630',(#664),#588,.F.);
#666=CARTESIAN_POINT('',(0.,7.,-9.5));
#667=DIRECTION('',(0.,0.,1.));
#668=DIRECTION('',(1.,0.,0.));
#669=AXIS2_PLACEMENT_3D('',#666,#667,#668);
#670=CIRCLE('',#669,1.5);
#671=CARTESIAN_POINT('',(1.5,7.,-9.5));
#672=VERTEX_POINT('',#671);
#673=EDGE_CURVE('E372',#672,#672,#670,.T.);
#674=ORIENTED_EDGE('',*,*,#673,.T.);
#675=EDGE_LOOP('',(#674));
#676=FACE_BOUND('',#675,.T.);
#677=ORIENTED_EDGE('',*,*,#561,.T.);
#678=DIRECTION('',(1.,0.,0.));
#679=VECTOR('',#678,1.);
#680=CARTESIAN_POINT('',(-7.5,5.,-9.5));
#681=LINE('',#680,#679);
#682=EDGE_CURVE('E332',#654,#558,#681,.T.);
#683=ORIENTED_EDGE('',*,*,#682,.F.);
#684=ORIENTED_EDGE('',*,*,#655,.T.);
#685=ORIENTED_EDGE('',*,*,#529,.T.);
#686=EDGE_LOOP('',(#677,#683,#684,#685));
#687=FACE_BOUND('',#686,.T.);
#688=ADVANCED_FACE('F620',(#676,#687),#190,.F.);
#689=CARTESIAN_POINT('',(-3.,-7.,0.));
#690=DIRECTION('',(-1.,0.,0.));
#691=DIRECTION('',(0.,-1.,0.));
#692=AXIS2_PLACEMENT_3D('',#689,#690,#691);
#693=PLANE('',#692);
#694=ORIENTED_EDGE('',*,*,#121,.T.);
#695=ORIENTED_EDGE('',*,*,#493,.F.);
#696=DIRECTION('',(0.,-1.,0.));
#697=VECTOR('',#696,1.);
#698=CARTESIAN_POINT('',(-3.,-7.,0.));
#699=LINE('',#698,#697);
#700=CARTESIAN_POINT('',(-3.,-7.,0.));
#701=VERTEX_POINT('',#700);
#702=EDGE_CURVE('E420',#701,#484,#699,.T.);
#703=ORIENTED_EDGE('',*,*,#702,.F.);
#704=DIRECTION('',(0.,0.,1.));
#705=VECTOR('',#704,1.);
#706=CARTESIAN_POINT('',(-3.,-7.,0.));
#707=LINE('',#706,#705);
#708=EDGE_CURVE('E428',#701,#120,#707,.T.);
#709=ORIENTED_EDGE('',*,*,#708,.T.);
#710=EDGE_LOOP('',(#694,#695,#703,#709));
#711=FACE_BOUND('',#710,.T.);
#712=ADVANCED_FACE('F616',(#711),#693,.F.);
#713=CARTESIAN_POINT('',(0.,-7.,0.));
#714=DIRECTION('',(0.,0.,1.));
#715=DIRECTION('',(1.,0.,0.));
#716=AXIS2_PLACEMENT_3D('',#713,#714,#715);
#717=CYLINDRICAL_SURFACE('',#716,3.);
#718=ORIENTED_EDGE('',*,*,#130,.T.);
#719=ORIENTED_EDGE('',*,*,#708,.F.);
#720=CARTESIAN_POINT('',(0.,-7.,0.));
#721=DIRECTION('',(0.,0.,1.));
#722=DIRECTION('',(1.,0.,0.));
#723=AXIS2_PLACEMENT_3D('',#720,#721,#722);
#724=CIRCLE('',#723,3.);
#725=CARTESIAN_POINT('',(3.,-7.,0.));
#726=VERTEX_POINT('',#725);
#727=EDGE_CURVE('E417',#726,#701,#724,.T.);
#728=ORIENTED_EDGE('',*,*,#727,.F.);
#729=DIRECTION('',(0.,0.,1.));
#730=VECTOR('',#729,1.);
#731=CARTESIAN_POINT('',(3.,-7.,0.));
#732=LINE('',#731,#730);
#733=EDGE_CURVE('E430',#726,#129,#732,.T.);
#734=ORIENTED_EDGE('',*,*,#733,.T.);
#735=EDGE_LOOP('',(#718,#719,#728,#734));
#736=FACE_BOUND('',#735,.T.);
#737=ADVANCED_FACE('F619',(#736),#717,.F.);
#738=CARTESIAN_POINT('',(3.,-7.,0.));
#739=DIRECTION('',(1.,0.,0.));
#740=DIRECTION('',(0.,1.,0.));
#741=AXIS2_PLACEMENT_3D('',#738,#739,#740);
#742=PLANE('',#741);
#743=ORIENTED_EDGE('',*,*,#138,.T.);
#744=ORIENTED_EDGE('',*,*,#733,.F.);
#745=DIRECTION('',(0.,1.,0.));
#746=VECTOR('',#745,1.);
#747=CARTESIAN_POINT('',(3.,-7.,0.));
#748=LINE('',#747,#746);
#749=EDGE_CURVE('E414',#486,#726,#748,.T.);
#750=ORIENTED_EDGE('',*,*,#749,.F.);
#751=ORIENTED_EDGE('',*,*,#504,.T.);
#752=EDGE_LOOP('',(#743,#744,#750,#751));
#753=FACE_BOUND('',#752,.T.);
#754=ADVANCED_FACE('F614',(#753),#742,.F.);
#755=CARTESIAN_POINT('',(0.,-7.,0.));
#756=DIRECTION('',(0.,0.,1.));
#757=DIRECTION('',(1.,0.,0.));
#758=AXIS2_PLACEMENT_3D('',#755,#756,#757);
#759=PLANE('',#758);
#760=CARTESIAN_POINT('',(0.,-7.,0.));
#761=DIRECTION('',(0.,0.,1.));
#762=DIRECTION('',(1.,0.,0.));
#763=AXIS2_PLACEMENT_3D('',#760,#761,#762);
#764=CIRCLE('',#763,1.5);
#765=CARTESIAN_POINT('',(1.5,-7.,0.));
#766=VERTEX_POINT('',#765);
#767=EDGE_CURVE('E357',#766,#766,#764,.T.);
#768=ORIENTED_EDGE('',*,*,#767,.F.);
#769=EDGE_LOOP('',(#768));
#770=FACE_BOUND('',#769,.T.);
#771=ORIENTED_EDGE('',*,*,#487,.T.);
#772=ORIENTED_EDGE('',*,*,#749,.T.);
#773=ORIENTED_EDGE('',*,*,#727,.T.);
#774=ORIENTED_EDGE('',*,*,#702,.T.);
#775=EDGE_LOOP('',(#771,#772,#773,#774));
#776=FACE_BOUND('',#775,.T.);
#777=ADVANCED_FACE('F610',(#770,#776),#759,.T.);
#778=CARTESIAN_POINT('',(0.,7.,0.));
#779=DIRECTION('',(0.,0.,1.));
#780=DIRECTION('',(1.,0.,0.));
#781=AXIS2_PLACEMENT_3D('',#778,#779,#780);
#782=CYLINDRICAL_SURFACE('',#781,3.);
#783=ORIENTED_EDGE('',*,*,#170,.T.);
#784=DIRECTION('',(0.,0.,1.));
#785=VECTOR('',#784,1.);
#786=CARTESIAN_POINT('',(3.,7.,0.));
#787=LINE('',#786,#785);
#788=CARTESIAN_POINT('',(3.,7.,0.));
#789=VERTEX_POINT('',#788);
#790=EDGE_CURVE('E393',#789,#162,#787,.T.);
#791=ORIENTED_EDGE('',*,*,#790,.F.);
#792=CARTESIAN_POINT('',(0.,7.,0.));
#793=DIRECTION('',(0.,0.,1.));
#794=DIRECTION('',(-1.,0.,0.));
#795=AXIS2_PLACEMENT_3D('',#792,#793,#794);
#796=CIRCLE('',#795,3.);
#797=CARTESIAN_POINT('',(-3.,7.,0.));
#798=VERTEX_POINT('',#797);
#799=EDGE_CURVE('E382',#798,#789,#796,.T.);
#800=ORIENTED_EDGE('',*,*,#799,.F.);
#801=DIRECTION('',(0.,0.,1.));
#802=VECTOR('',#801,1.);
#803=CARTESIAN_POINT('',(-3.,7.,0.));
#804=LINE('',#803,#802);
#805=EDGE_CURVE('E394',#798,#87,#804,.T.);
#806=ORIENTED_EDGE('',*,*,#805,.T.);
#807=EDGE_LOOP('',(#783,#791,#800,#806));
#808=FACE_BOUND('',#807,.T.);
#809=ADVANCED_FACE('F603',(#808),#782,.F.);
#810=CARTESIAN_POINT('',(-3.,7.,0.));
#811=DIRECTION('',(-1.,0.,0.));
#812=DIRECTION('',(0.,-1.,0.));
#813=AXIS2_PLACEMENT_3D('',#810,#811,#812);
#814=PLANE('',#813);
#815=ORIENTED_EDGE('',*,*,#88,.T.);
#816=ORIENTED_EDGE('',*,*,#805,.F.);
#817=DIRECTION('',(0.,-1.,0.));
#818=VECTOR('',#817,1.);
#819=CARTESIAN_POINT('',(-3.,7.,0.));
#820=LINE('',#819,#818);
#821=EDGE_CURVE('E390',#428,#798,#820,.T.);
#822=ORIENTED_EDGE('',*,*,#821,.F.);
#823=ORIENTED_EDGE('',*,*,#429,.T.);
#824=EDGE_LOOP('',(#815,#816,#822,#823));
#825=FACE_BOUND('',#824,.T.);
#826=ADVANCED_FACE('F600',(#825),#814,.F.);
#827=CARTESIAN_POINT('',(3.,7.,0.));
#828=DIRECTION('',(1.,0.,0.));
#829=DIRECTION('',(0.,1.,0.));
#830=AXIS2_PLACEMENT_3D('',#827,#828,#829);
#831=PLANE('',#830);
#832=ORIENTED_EDGE('',*,*,#163,.T.);
#833=ORIENTED_EDGE('',*,*,#443,.F.);
#834=DIRECTION('',(0.,1.,0.));
#835=VECTOR('',#834,1.);
#836=CARTESIAN_POINT('',(3.,7.,0.));
#837=LINE('',#836,#835);
#838=EDGE_CURVE('E385',#789,#436,#837,.T.);
#839=ORIENTED_EDGE('',*,*,#838,.F.);
#840=ORIENTED_EDGE('',*,*,#790,.T.);
#841=EDGE_LOOP('',(#832,#833,#839,#840));
#842=FACE_BOUND('',#841,.T.);
#843=ADVANCED_FACE('F598',(#842),#831,.F.);
#844=CARTESIAN_POINT('',(0.,7.,0.));
#845=DIRECTION('',(0.,0.,-1.));
#846=DIRECTION('',(-1.,0.,0.));
#847=AXIS2_PLACEMENT_3D('',#844,#845,#846);
#848=PLANE('',#847);
#849=CARTESIAN_POINT('',(0.,7.,0.));
#850=DIRECTION('',(0.,0.,1.));
#851=DIRECTION('',(1.,0.,0.));
#852=AXIS2_PLACEMENT_3D('',#849,#850,#851);
#853=CIRCLE('',#852,1.5);
#854=CARTESIAN_POINT('',(1.5,7.,0.));
#855=VERTEX_POINT('',#854);
#856=EDGE_CURVE('E369',#855,#855,#853,.T.);
#857=ORIENTED_EDGE('',*,*,#856,.F.);
#858=EDGE_LOOP('',(#857));
#859=FACE_BOUND('',#858,.T.);
#860=ORIENTED_EDGE('',*,*,#799,.T.);
#861=ORIENTED_EDGE('',*,*,#838,.T.);
#862=ORIENTED_EDGE('',*,*,#437,.T.);
#863=ORIENTED_EDGE('',*,*,#821,.T.);
#864=EDGE_LOOP('',(#860,#861,#862,#863));
#865=FACE_BOUND('',#864,.T.);
#866=ADVANCED_FACE('F594',(#859,#865),#848,.F.);
#867=CARTESIAN_POINT('',(0.,7.,-9.5));
#868=DIRECTION('',(0.,0.,1.));
#869=DIRECTION('',(1.,0.,0.));
#870=AXIS2_PLACEMENT_3D('',#867,#868,#869);
#871=CYLINDRICAL_SURFACE('',#870,1.5);
#872=ORIENTED_EDGE('',*,*,#673,.F.);
#873=EDGE_LOOP('',(#872));
#874=FACE_BOUND('',#873,.T.);
#875=ORIENTED_EDGE('',*,*,#856,.T.);
#876=EDGE_LOOP('',(#875));
#877=FACE_BOUND('',#876,.T.);
#878=ADVANCED_FACE('F590',(#874,#877),#871,.F.);
#879=CARTESIAN_POINT('',(0.,-7.,-9.5));
#880=DIRECTION('',(0.,0.,1.));
#881=DIRECTION('',(1.,0.,0.));
#882=AXIS2_PLACEMENT_3D('',#879,#880,#881);
#883=CYLINDRICAL_SURFACE('',#882,1.5);
#884=ORIENTED_EDGE('',*,*,#198,.F.);
#885=EDGE_LOOP('',(#884));
#886=FACE_BOUND('',#885,.T.);
#887=ORIENTED_EDGE('',*,*,#767,.T.);
#888=EDGE_LOOP('',(#887));
#889=FACE_BOUND('',#888,.T.);
#890=ADVANCED_FACE('F583',(#886,#889),#883,.F.);
#891=CARTESIAN_POINT('',(-7.5,-5.,-4.5));
#892=DIRECTION('',(0.,-1.,0.));
#893=DIRECTION('',(1.,0.,0.));
#894=AXIS2_PLACEMENT_3D('',#891,#892,#893);
#895=PLANE('',#894);
#896=ORIENTED_EDGE('',*,*,#216,.T.);
#897=ORIENTED_EDGE('',*,*,#603,.F.);
#898=DIRECTION('',(-1.,0.,0.));
#899=VECTOR('',#898,1.);
#900=CARTESIAN_POINT('',(-7.5,-5.,-4.5));
#901=LINE('',#900,#899);
#902=EDGE_CURVE('E350',#31,#594,#901,.T.);
#903=ORIENTED_EDGE('',*,*,#902,.F.);
#904=ORIENTED_EDGE('',*,*,#70,.T.);
#905=EDGE_LOOP('',(#896,#897,#903,#904));
#906=FACE_BOUND('',#905,.T.);
#907=ADVANCED_FACE('F580',(#906),#895,.F.);
#908=CARTESIAN_POINT('',(-7.5,5.,-4.5));
#909=DIRECTION('',(0.,1.,0.));
#910=DIRECTION('',(-1.,0.,0.));
#911=AXIS2_PLACEMENT_3D('',#908,#909,#910);
#912=PLANE('',#911);
#913=ORIENTED_EDGE('',*,*,#682,.T.);
#914=ORIENTED_EDGE('',*,*,#559,.F.);
#915=DIRECTION('',(1.,0.,0.));
#916=VECTOR('',#915,1.);
#917=CARTESIAN_POINT('',(-7.5,5.,-4.5));
#918=LINE('',#917,#916);
#919=EDGE_CURVE('E343',#596,#550,#918,.T.);
#920=ORIENTED_EDGE('',*,*,#919,.F.);
#921=ORIENTED_EDGE('',*,*,#661,.T.);
#922=EDGE_LOOP('',(#913,#914,#920,#921));
#923=FACE_BOUND('',#922,.T.);
#924=ADVANCED_FACE('F578',(#923),#912,.F.);
#925=CARTESIAN_POINT('',(-7.5,5.,-4.5));
#926=DIRECTION('',(0.,0.,-1.));
#927=DIRECTION('',(-1.,0.,0.));
#928=AXIS2_PLACEMENT_3D('',#925,#926,#927);
#929=PLANE('',#928);
#930=CARTESIAN_POINT('',(10.,0.,-4.5));
#931=DIRECTION('',(0.,0.,-1.));
#932=DIRECTION('',(-1.,0.,0.));
#933=AXIS2_PLACEMENT_3D('',#930,#931,#932);
#934=CIRCLE('',#933,5.5);
#935=EDGE_CURVE('E502',#29,#546,#934,.T.);
#936=ORIENTED_EDGE('',*,*,#935,.F.);
#937=ORIENTED_EDGE('',*,*,#32,.T.);
#938=ORIENTED_EDGE('',*,*,#902,.T.);
#939=ORIENTED_EDGE('',*,*,#597,.T.);
#940=ORIENTED_EDGE('',*,*,#919,.T.);
#941=ORIENTED_EDGE('',*,*,#551,.T.);
#942=EDGE_LOOP('',(#936,#937,#938,#939,#940,#941));
#943=FACE_BOUND('',#942,.T.);
#944=ADVANCED_FACE('F574',(#943),#929,.T.);
#945=CARTESIAN_POINT('',(-7.5,0.,-0.5));
#946=DIRECTION('',(0.,0.,-1.));
#947=DIRECTION('',(-1.,0.,0.));
#948=AXIS2_PLACEMENT_3D('',#945,#946,#947);
#949=CYLINDRICAL_SURFACE('',#948,9.);
#950=ORIENTED_EDGE('',*,*,#295,.T.);
#951=DIRECTION('',(0.,0.,-1.));
#952=VECTOR('',#951,1.);
#953=CARTESIAN_POINT('',(-16.4861003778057,-0.5,-0.5));
#954=LINE('',#953,#952);
#955=CARTESIAN_POINT('',(-16.4861003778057,-0.5,-0.5));
#956=VERTEX_POINT('',#955);
#957=EDGE_CURVE('E329',#956,#285,#954,.T.);
#958=ORIENTED_EDGE('',*,*,#957,.F.);
#959=CARTESIAN_POINT('',(-7.5,0.,-0.5));
#960=DIRECTION('',(0.,0.,-1.));
#961=DIRECTION('',(1.,0.,0.));
#962=AXIS2_PLACEMENT_3D('',#959,#960,#961);
#963=CIRCLE('',#962,9.);
#964=EDGE_CURVE('E320',#612,#956,#963,.T.);
#965=ORIENTED_EDGE('',*,*,#964,.F.);
#966=ORIENTED_EDGE('',*,*,#613,.T.);
#967=EDGE_LOOP('',(#950,#958,#965,#966));
#968=FACE_BOUND('',#967,.T.);
#969=ADVANCED_FACE('F570',(#968),#949,.F.);
#970=CARTESIAN_POINT('',(-7.5,-0.5,-0.5));
#971=DIRECTION('',(0.,1.,0.));
#972=DIRECTION('',(-1.,0.,0.));
#973=AXIS2_PLACEMENT_3D('',#970,#971,#972);
#974=PLANE('',#973);
#975=ORIENTED_EDGE('',*,*,#286,.T.);
#976=ORIENTED_EDGE('',*,*,#627,.F.);
#977=DIRECTION('',(1.,0.,0.));
#978=VECTOR('',#977,1.);
#979=CARTESIAN_POINT('',(-7.5,-0.5,-0.5));
#980=LINE('',#979,#978);
#981=EDGE_CURVE('E323',#956,#620,#980,.T.);
#982=ORIENTED_EDGE('',*,*,#981,.F.);
#983=ORIENTED_EDGE('',*,*,#957,.T.);
#984=EDGE_LOOP('',(#975,#976,#982,#983));
#985=FACE_BOUND('',#984,.T.);
#986=ADVANCED_FACE('F566',(#985),#974,.F.);
#987=CARTESIAN_POINT('',(-7.5,0.,-0.5));
#988=DIRECTION('',(0.,0.,1.));
#989=DIRECTION('',(1.,0.,0.));
#990=AXIS2_PLACEMENT_3D('',#987,#988,#989);
#991=PLANE('',#990);
#992=ORIENTED_EDGE('',*,*,#964,.T.);
#993=ORIENTED_EDGE('',*,*,#981,.T.);
#994=ORIENTED_EDGE('',*,*,#621,.T.);
#995=EDGE_LOOP('',(#992,#993,#994));
#996=FACE_BOUND('',#995,.T.);
#997=ADVANCED_FACE('F559',(#996),#991,.F.);
#998=CARTESIAN_POINT('',(-7.5,0.,-0.5));
#999=DIRECTION('',(0.,0.,-1.));
#1000=DIRECTION('',(-1.,0.,0.));
#1001=AXIS2_PLACEMENT_3D('',#998,#999,#1000);
#1002=CYLINDRICAL_SURFACE('',#1001,9.);
#1003=ORIENTED_EDGE('',*,*,#262,.T.);
#1004=ORIENTED_EDGE('',*,*,#650,.F.);
#1005=CARTESIAN_POINT('',(-7.5,0.,-0.5));
#1006=DIRECTION('',(0.,0.,-1.));
#1007=DIRECTION('',(1.,0.,0.));
#1008=AXIS2_PLACEMENT_3D('',#1005,#1006,#1007);
#1009=CIRCLE('',#1008,9.);
#1010=CARTESIAN_POINT('',(-16.4861003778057,0.5,-0.5));
#1011=VERTEX_POINT('',#1010);
#1012=EDGE_CURVE('E305',#1011,#643,#1009,.T.);
#1013=ORIENTED_EDGE('',*,*,#1012,.F.);
#1014=DIRECTION('',(0.,0.,-1.));
#1015=VECTOR('',#1014,1.);
#1016=CARTESIAN_POINT('',(-16.4861003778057,0.5,-0.5));
#1017=LINE('',#1016,#1015);
#1018=EDGE_CURVE('E313',#1011,#261,#1017,.T.);
#1019=ORIENTED_EDGE('',*,*,#1018,.T.);
#1020=EDGE_LOOP('',(#1003,#1004,#1013,#1019));
#1021=FACE_BOUND('',#1020,.T.);
#1022=ADVANCED_FACE('F556',(#1021),#1002,.F.);
#1023=CARTESIAN_POINT('',(-7.5,0.5,-0.5));
#1024=DIRECTION('',(0.,-1.,0.));
#1025=DIRECTION('',(1.,0.,0.));
#1026=AXIS2_PLACEMENT_3D('',#1023,#1024,#1025);
#1027=PLANE('',#1026);
#1028=ORIENTED_EDGE('',*,*,#270,.T.);
#1029=ORIENTED_EDGE('',*,*,#1018,.F.);
#1030=DIRECTION('',(-1.,0.,0.));
#1031=VECTOR('',#1030,1.);
#1032=CARTESIAN_POINT('',(-7.5,0.5,-0.5));
#1033=LINE('',#1032,#1031);
#1034=EDGE_CURVE('E302',#635,#1011,#1033,.T.);
#1035=ORIENTED_EDGE('',*,*,#1034,.F.);
#1036=ORIENTED_EDGE('',*,*,#636,.T.);
#1037=EDGE_LOOP('',(#1028,#1029,#1035,#1036));
#1038=FACE_BOUND('',#1037,.T.);
#1039=ADVANCED_FACE('F554',(#1038),#1027,.F.);
#1040=CARTESIAN_POINT('',(-7.5,0.,-0.5));
#1041=DIRECTION('',(0.,0.,1.));
#1042=DIRECTION('',(1.,0.,0.));
#1043=AXIS2_PLACEMENT_3D('',#1040,#1041,#1042);
#1044=PLANE('',#1043);
#1045=ORIENTED_EDGE('',*,*,#644,.T.);
#1046=ORIENTED_EDGE('',*,*,#1034,.T.);
#1047=ORIENTED_EDGE('',*,*,#1012,.T.);
#1048=EDGE_LOOP('',(#1045,#1046,#1047));
#1049=FACE_BOUND('',#1048,.T.);
#1050=ADVANCED_FACE('F550',(#1049),#1044,.F.);
#1051=CARTESIAN_POINT('',(10.,0.,12.5));
#1052=DIRECTION('',(0.,0.,-1.));
#1053=DIRECTION('',(-1.,0.,0.));
#1054=AXIS2_PLACEMENT_3D('',#1051,#1052,#1053);
#1055=CYLINDRICAL_SURFACE('',#1054,5.5);
#1056=CARTESIAN_POINT('',(10.,0.,12.5));
#1057=DIRECTION('',(0.,0.,1.));
#1058=DIRECTION('',(1.,0.,0.));
#1059=AXIS2_PLACEMENT_3D('',#1056,#1057,#1058);
#1060=CIRCLE('',#1059,5.5);
#1061=CARTESIAN_POINT('',(15.5,0.,12.5));
#1062=VERTEX_POINT('',#1061);
#1063=EDGE_CURVE('E291',#1062,#1062,#1060,.T.);
#1064=ORIENTED_EDGE('',*,*,#1063,.F.);
#1065=EDGE_LOOP('',(#1064));
#1066=FACE_BOUND('',#1065,.T.);
#1067=ORIENTED_EDGE('',*,*,#181,.T.);
#1068=EDGE_LOOP('',(#1067));
#1069=FACE_BOUND('',#1068,.T.);
#1070=ADVANCED_FACE('F546',(#1066,#1069),#1055,.T.);
#1071=CARTESIAN_POINT('',(10.,0.,-9.5));
#1072=DIRECTION('',(0.,0.,1.));
#1073=DIRECTION('',(1.,0.,0.));
#1074=AXIS2_PLACEMENT_3D('',#1071,#1072,#1073);
#1075=CYLINDRICAL_SURFACE('',#1074,3.5);
#1076=CARTESIAN_POINT('',(10.,0.,10.5));
#1077=DIRECTION('',(0.,0.,1.));
#1078=DIRECTION('',(1.,0.,0.));
#1079=AXIS2_PLACEMENT_3D('',#1076,#1077,#1078);
#1080=CIRCLE('',#1079,3.5);
#1081=CARTESIAN_POINT('',(13.5,0.,10.5));
#1082=VERTEX_POINT('',#1081);
#1083=EDGE_CURVE('E11',#1082,#1082,#1080,.T.);
#1084=ORIENTED_EDGE('',*,*,#1083,.T.);
#1085=EDGE_LOOP('',(#1084));
#1086=FACE_BOUND('',#1085,.T.);
#1087=CARTESIAN_POINT('',(10.,0.,-0.5));
#1088=DIRECTION('',(0.,0.,1.));
#1089=DIRECTION('',(1.,0.,0.));
#1090=AXIS2_PLACEMENT_3D('',#1087,#1088,#1089);
#1091=CIRCLE('',#1090,3.5);
#1092=CARTESIAN_POINT('',(13.5,0.,-0.5));
#1093=VERTEX_POINT('',#1092);
#1094=EDGE_CURVE('E44',#1093,#1093,#1091,.F.);
#1095=ORIENTED_EDGE('',*,*,#1094,.T.);
#1096=EDGE_LOOP('',(#1095));
#1097=FACE_BOUND('',#1096,.T.);
#1098=ADVANCED_FACE('F542',(#1086,#1097),#1075,.F.);
#1099=CARTESIAN_POINT('',(10.,0.,13.056349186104));
#1100=DIRECTION('',(0.,0.,-1.));
#1101=DIRECTION('',(-1.,0.,0.));
#1102=AXIS2_PLACEMENT_3D('',#1099,#1100,#1101);
#1103=CYLINDRICAL_SURFACE('',#1102,5.5);
#1104=ORIENTED_EDGE('',*,*,#935,.T.);
#1105=ORIENTED_EDGE('',*,*,#547,.F.);
#1106=CARTESIAN_POINT('',(10.,0.,-2.5));
#1107=DIRECTION('',(0.,0.,1.));
#1108=DIRECTION('',(1.,0.,0.));
#1109=AXIS2_PLACEMENT_3D('',#1106,#1107,#1108);
#1110=CIRCLE('',#1109,5.5);
#1111=EDGE_CURVE('E278',#39,#240,#1110,.F.);
#1112=ORIENTED_EDGE('',*,*,#1111,.F.);
#1113=ORIENTED_EDGE('',*,*,#40,.F.);
#1114=EDGE_LOOP('',(#1104,#1105,#1112,#1113));
#1115=FACE_BOUND('',#1114,.T.);
#1116=ADVANCED_FACE('F539',(#1115),#1103,.F.);
#1117=CARTESIAN_POINT('',(16.1602540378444,5.,-2.5));
#1118=DIRECTION('',(0.,1.,0.));
#1119=DIRECTION('',(-1.,0.,0.));
#1120=AXIS2_PLACEMENT_3D('',#1117,#1118,#1119);
#1121=PLANE('',#1120);
#1122=DIRECTION('',(0.,0.,1.));
#1123=VECTOR('',#1122,1.);
#1124=CARTESIAN_POINT('',(19.5,5.,-2.5));
#1125=LINE('',#1124,#1123);
#1126=CARTESIAN_POINT('',(19.5,5.,-0.5));
#1127=VERTEX_POINT('',#1126);
#1128=CARTESIAN_POINT('',(19.5,5.,0.));
#1129=VERTEX_POINT('',#1128);
#1130=EDGE_CURVE('E272',#1127,#1129,#1125,.T.);
#1131=ORIENTED_EDGE('',*,*,#1130,.F.);
#1132=CARTESIAN_POINT('',(19.5,5.,-0.5));
#1133=CARTESIAN_POINT('',(19.5000075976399,5.,-0.55298581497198));
#1134=CARTESIAN_POINT('',(19.4977190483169,5.,-0.605967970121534));
#1135=CARTESIAN_POINT('',(19.48860799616,5.,-0.711531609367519));
#1136=CARTESIAN_POINT('',(19.4817863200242,5.,-0.764113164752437));
#1137=CARTESIAN_POINT('',(19.4636910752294,5.,-0.868364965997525));
#1138=CARTESIAN_POINT('',(19.45242922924,5.,-0.920037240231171));
#1139=CARTESIAN_POINT('',(19.4255766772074,5.,-1.022230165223));
#1140=CARTESIAN_POINT('',(19.409985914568,5.,-1.07275080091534));
#1141=CARTESIAN_POINT('',(19.3569302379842,5.,-1.22203856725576));
#1142=CARTESIAN_POINT('',(19.3131620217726,5.,-1.31864468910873));
#1143=CARTESIAN_POINT('',(19.2104708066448,5.,-1.50337490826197));
#1144=CARTESIAN_POINT('',(19.1515423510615,5.,-1.5914959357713));
#1145=CARTESIAN_POINT('',(19.0186772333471,5.,-1.75964815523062));
#1146=CARTESIAN_POINT('',(18.9443659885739,5.,-1.83938312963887));
#1147=CARTESIAN_POINT('',(18.7842337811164,5.,-1.98625318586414));
#1148=CARTESIAN_POINT('',(18.6984112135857,5.,-2.05338650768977));
#1149=CARTESIAN_POINT('',(18.5111407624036,5.,-2.17841384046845));
#1150=CARTESIAN_POINT('',(18.4090111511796,5.,-2.23528514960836));
#1151=CARTESIAN_POINT('',(18.1971842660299,5.,-2.33271406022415));
#1152=CARTESIAN_POINT('',(18.0874803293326,5.,-2.37325707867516));
#1153=CARTESIAN_POINT('',(17.8653686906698,5.,-2.43716187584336));
#1154=CARTESIAN_POINT('',(17.7530454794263,5.,-2.46082043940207));
#1155=CARTESIAN_POINT('',(17.5264427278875,5.,-2.49223790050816));
#1156=CARTESIAN_POINT('',(17.4121681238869,5.,-2.50003223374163));
#1157=CARTESIAN_POINT('',(17.2979589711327,5.,-2.5));
#1158=B_SPLINE_CURVE_WITH_KNOTS('',3,(#1132,#1133,#1134,#1135,#1136,#1137,#1138,#1139,#1140,
#1141,#1142,#1143,#1144,#1145,#1146,#1147,#1148,#1149,#1150,#1151,#1152,#1153,#1154,#1155,#1156,
#1157),.UNSPECIFIED.,.F.,.F.,(4,2,2,2,2,2,2,2,2,2,2,2,4),(0.,0.158901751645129,
0.317774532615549,0.476230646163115,0.634688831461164,0.951264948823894,1.26795517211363,
1.59352767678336,1.91914561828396,2.2683705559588,2.61790670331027,2.96113655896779,
3.30359890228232),.UNSPECIFIED.);
#1159=EDGE_CURVE('E59',#1127,#310,#1158,.T.);
#1160=ORIENTED_EDGE('',*,*,#1159,.T.);
#1161=ORIENTED_EDGE('',*,*,#313,.T.);
#1162=ORIENTED_EDGE('',*,*,#391,.T.);
#1163=DIRECTION('',(-1.,0.,0.));
#1164=VECTOR('',#1163,1.);
#1165=CARTESIAN_POINT('',(16.1602540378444,5.,0.));
#1166=LINE('',#1165,#1164);
#1167=EDGE_CURVE('E261',#1129,#382,#1166,.T.);
#1168=ORIENTED_EDGE('',*,*,#1167,.F.);
#1169=EDGE_LOOP('',(#1131,#1160,#1161,#1162,#1168));
#1170=FACE_BOUND('',#1169,.T.);
#1171=ADVANCED_FACE('F516',(#1170),#1121,.T.);
#1172=CARTESIAN_POINT('',(7.5,0.,-2.5));
#1173=DIRECTION('',(0.,0.,1.));
#1174=DIRECTION('',(1.,0.,0.));
#1175=AXIS2_PLACEMENT_3D('',#1172,#1173,#1174);
#1176=CYLINDRICAL_SURFACE('',#1175,13.);
#1177=DIRECTION('',(0.,0.,1.));
#1178=VECTOR('',#1177,1.);
#1179=CARTESIAN_POINT('',(19.5,-5.,-2.5));
#1180=LINE('',#1179,#1178);
#1181=CARTESIAN_POINT('',(19.5,-5.,-0.5));
#1182=VERTEX_POINT('',#1181);
#1183=CARTESIAN_POINT('',(19.5,-5.,0.));
#1184=VERTEX_POINT('',#1183);
#1185=EDGE_CURVE('E251',#1182,#1184,#1180,.T.);
#1186=ORIENTED_EDGE('',*,*,#1185,.F.);
#1187=CARTESIAN_POINT('',(7.5,0.,-0.5));
#1188=DIRECTION('',(0.,0.,1.));
#1189=DIRECTION('',(1.,0.,0.));
#1190=AXIS2_PLACEMENT_3D('',#1187,#1188,#1189);
#1191=CIRCLE('',#1190,13.);
#1192=EDGE_CURVE('E504',#1182,#1127,#1191,.T.);
#1193=ORIENTED_EDGE('',*,*,#1192,.T.);
#1194=ORIENTED_EDGE('',*,*,#1130,.T.);
#1195=CARTESIAN_POINT('',(7.5,0.,0.));
#1196=DIRECTION('',(0.,0.,1.));
#1197=DIRECTION('',(1.,0.,0.));
#1198=AXIS2_PLACEMENT_3D('',#1195,#1196,#1197);
#1199=CIRCLE('',#1198,13.);
#1200=EDGE_CURVE('E255',#1184,#1129,#1199,.T.);
#1201=ORIENTED_EDGE('',*,*,#1200,.F.);
#1202=EDGE_LOOP('',(#1186,#1193,#1194,#1201));
#1203=FACE_BOUND('',#1202,.T.);
#1204=ADVANCED_FACE('F538',(#1203),#1176,.T.);
#1205=CARTESIAN_POINT('',(16.1602540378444,-5.,-2.5));
#1206=DIRECTION('',(0.,-1.,0.));
#1207=DIRECTION('',(1.,0.,0.));
#1208=AXIS2_PLACEMENT_3D('',#1205,#1206,#1207);
#1209=PLANE('',#1208);
#1210=ORIENTED_EDGE('',*,*,#330,.T.);
#1211=CARTESIAN_POINT('',(17.2979589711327,-5.,-2.5));
#1212=CARTESIAN_POINT('',(17.3654327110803,-5.,-2.49999601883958));
#1213=CARTESIAN_POINT('',(17.4328800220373,-5.,-2.4972892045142));
#1214=CARTESIAN_POINT('',(17.567353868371,-5.,-2.48639742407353));
#1215=CARTESIAN_POINT('',(17.6343802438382,-5.,-2.47821048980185));
#1216=CARTESIAN_POINT('',(17.83456425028,-5.,-2.44526408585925));
#1217=CARTESIAN_POINT('',(17.9664561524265,-5.,-2.41211817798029));
#1218=CARTESIAN_POINT('',(18.2228324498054,-5.,-2.3233624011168));
#1219=CARTESIAN_POINT('',(18.3472968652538,-5.,-2.26769482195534));
#1220=CARTESIAN_POINT('',(18.5838461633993,-5.,-2.1345998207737));
#1221=CARTESIAN_POINT('',(18.6959520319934,-5.,-2.05721010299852));
#1222=CARTESIAN_POINT('',(18.8951684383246,-5.,-1.88909235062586));
#1223=CARTESIAN_POINT('',(18.9835431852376,-5.,-1.79986421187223));
#1224=CARTESIAN_POINT('',(19.1422149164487,-5.,-1.6064543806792));
#1225=CARTESIAN_POINT('',(19.2125125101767,-5.,-1.50227319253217));
#1226=CARTESIAN_POINT('',(19.3261186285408,-5.,-1.29254820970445));
#1227=CARTESIAN_POINT('',(19.3713274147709,-5.,-1.18802964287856));
#1228=CARTESIAN_POINT('',(19.4421256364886,-5.,-0.972643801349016));
#1229=CARTESIAN_POINT('',(19.4677531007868,-5.,-0.861789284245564));
#1230=CARTESIAN_POINT('',(19.4886960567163,-5.,-0.708282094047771));
#1231=CARTESIAN_POINT('',(19.4929353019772,-5.,-0.6667052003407));
#1232=CARTESIAN_POINT('',(19.498583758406,-5.,-0.58342592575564));
#1233=CARTESIAN_POINT('',(19.4999974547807,-5.,-0.541723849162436));
#1234=CARTESIAN_POINT('',(19.5000000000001,-5.,-0.500000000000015));
#1235=B_SPLINE_CURVE_WITH_KNOTS('',3,(#1211,#1212,#1213,#1214,#1215,#1216,#1217,#1218,#1219,
#1220,#1221,#1222,#1223,#1224,#1225,#1226,#1227,#1228,#1229,#1230,#1231,#1232,#1233,#1234),
.UNSPECIFIED.,.F.,.F.,(4,2,2,2,2,2,2,2,2,2,2,4),(0.,0.202310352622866,0.40469340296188,
0.810557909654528,1.2174690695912,1.62367825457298,1.99838451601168,2.37307814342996,
2.71297149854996,3.05220305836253,3.17750639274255,3.3026106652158),.UNSPECIFIED.);
#1236=EDGE_CURVE('E529',#321,#1182,#1235,.T.);
#1237=ORIENTED_EDGE('',*,*,#1236,.T.);
#1238=ORIENTED_EDGE('',*,*,#1185,.T.);
#1239=DIRECTION('',(1.,0.,0.));
#1240=VECTOR('',#1239,1.);
#1241=CARTESIAN_POINT('',(16.1602540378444,-5.,0.));
#1242=LINE('',#1241,#1240);
#1243=EDGE_CURVE('E245',#384,#1184,#1242,.T.);
#1244=ORIENTED_EDGE('',*,*,#1243,.F.);
#1245=ORIENTED_EDGE('',*,*,#412,.F.);
#1246=EDGE_LOOP('',(#1210,#1237,#1238,#1244,#1245));
#1247=FACE_BOUND('',#1246,.T.);
#1248=ADVANCED_FACE('F247',(#1247),#1209,.T.);
#1249=CARTESIAN_POINT('',(7.5,0.,0.));
#1250=DIRECTION('',(0.,0.,1.));
#1251=DIRECTION('',(1.,0.,0.));
#1252=AXIS2_PLACEMENT_3D('',#1249,#1250,#1251);
#1253=PLANE('',#1252);
#1254=ORIENTED_EDGE('',*,*,#385,.T.);
#1255=ORIENTED_EDGE('',*,*,#1243,.T.);
#1256=ORIENTED_EDGE('',*,*,#1200,.T.);
#1257=ORIENTED_EDGE('',*,*,#1167,.T.);
#1258=EDGE_LOOP('',(#1254,#1255,#1256,#1257));
#1259=FACE_BOUND('',#1258,.T.);
#1260=ADVANCED_FACE('F259',(#1259),#1253,.T.);
#1261=CARTESIAN_POINT('',(7.5,0.,-0.5));
#1262=DIRECTION('',(0.,0.,1.));
#1263=DIRECTION('',(1.,0.,0.));
#1264=AXIS2_PLACEMENT_3D('',#1261,#1262,#1263);
#1265=TOROIDAL_SURFACE('',#1264,11.,2.);
#1266=ORIENTED_EDGE('',*,*,#1236,.F.);
#1267=ORIENTED_EDGE('',*,*,#322,.F.);
#1268=ORIENTED_EDGE('',*,*,#1159,.F.);
#1269=ORIENTED_EDGE('',*,*,#1192,.F.);
#1270=EDGE_LOOP('',(#1266,#1267,#1268,#1269));
#1271=FACE_BOUND('',#1270,.T.);
#1272=ADVANCED_FACE('F520',(#1271),#1265,.T.);
#1273=CARTESIAN_POINT('',(10.,0.,10.5));
#1274=DIRECTION('',(0.,0.,1.));
#1275=DIRECTION('',(1.,0.,0.));
#1276=AXIS2_PLACEMENT_3D('',#1273,#1274,#1275);
#1277=TOROIDAL_SURFACE('',#1276,5.5,2.);
#1278=ORIENTED_EDGE('',*,*,#1063,.T.);
#1279=EDGE_LOOP('',(#1278));
#1280=FACE_BOUND('',#1279,.T.);
#1281=ORIENTED_EDGE('',*,*,#1083,.F.);
#1282=EDGE_LOOP('',(#1281));
#1283=FACE_BOUND('',#1282,.T.);
#1284=ADVANCED_FACE('F524',(#1280,#1283),#1277,.T.);
#1285=CARTESIAN_POINT('',(10.,0.,-0.5));
#1286=DIRECTION('',(0.,0.,1.));
#1287=DIRECTION('',(1.,0.,0.));
#1288=AXIS2_PLACEMENT_3D('',#1285,#1286,#1287);
#1289=TOROIDAL_SURFACE('',#1288,5.5,2.);
#1290=ORIENTED_EDGE('',*,*,#1094,.F.);
#1291=EDGE_LOOP('',(#1290));
#1292=FACE_BOUND('',#1291,.T.);
#1293=ORIENTED_EDGE('',*,*,#241,.F.);
#1294=ORIENTED_EDGE('',*,*,#1111,.T.);
#1295=EDGE_LOOP('',(#1293,#1294));
#1296=FACE_BOUND('',#1295,.T.);
#1297=ADVANCED_FACE('F711',(#1292,#1296),#1289,.T.);
#1298=CLOSED_SHELL('',(#74,#185,#227,#370,#416,#456,#473,#508,#539,#566,#583,#665,#688,#712,
#737,#754,#777,#809,#826,#843,#866,#878,#890,#907,#924,#944,#969,#986,#997,#1022,#1039,#1050,
#1070,#1098,#1116,#1171,#1204,#1248,#1260,#1272,#1284,#1297));
#1299=MANIFOLD_SOLID_BREP('B2',#1298);
#1300=ADVANCED_BREP_SHAPE_REPRESENTATION('',(#18,#1299),#14);
#1301=SHAPE_DEFINITION_REPRESENTATION(#9,#1300);
ENDSEC;
END-ISO-10303-21;
